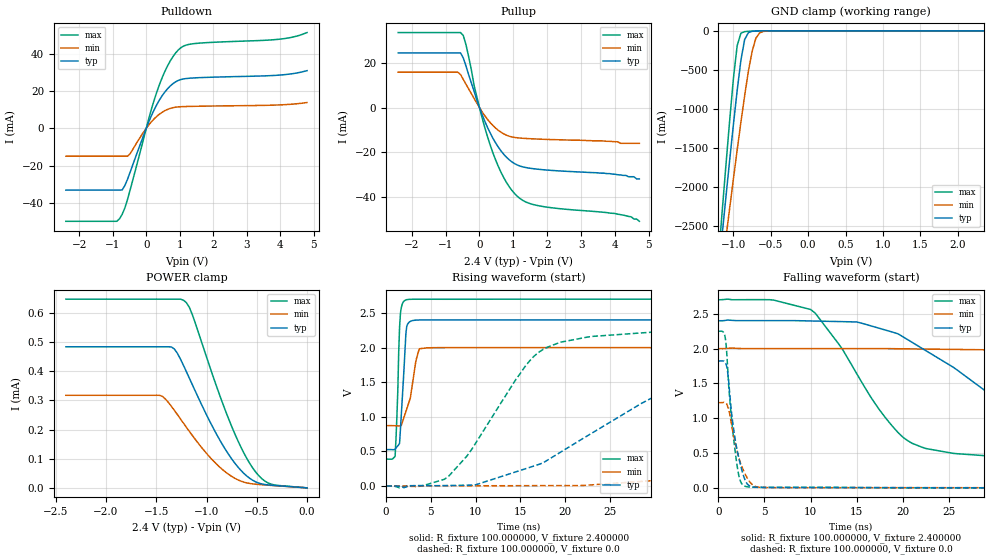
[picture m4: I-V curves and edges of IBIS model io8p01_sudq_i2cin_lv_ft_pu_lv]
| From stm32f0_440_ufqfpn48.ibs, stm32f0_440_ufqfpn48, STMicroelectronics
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|   Model io8p01_sudq_i2cin_lv_ft_pu_lv
[Model]  io8p01_sudq_i2cin_lv_ft_pu_lv
Model_type I/O
Polarity   Non-Inverting
Enable   Active-Low
Vinl =   0.720000V
Vinh =   1.680000V
Vmeas =  1.200000V
Cref =   50.000000pF
Rref =   100.000000M
Vref =   0.0V
C_comp   2.067900pF   1.988600pF   2.164800pF
[Temperature Range]   25.000000   0.125000k   -40.000000
[Pullup Reference]   2.400000V   2.000000V   2.700000V
[Pulldown Reference]   0.0V   0.0V   0.0V
[POWER Clamp Reference]   2.400000V   2.000000V   2.700000V
[GND Clamp Reference]   0.0V   0.0V   0.0V
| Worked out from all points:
|   slope of the pulldown table from 0 to 0.36 V, typ, clamps not added: 25.5 ohm
|   slope of the pullup table from 0 to 0.36 V, typ, clamps not added: 28.4 ohm
|   GND clamp passes 1 mA (typ) near -0.64 V on its own axis
|   rising waveform, R_fixture 100.000000, V_fixture 2.400000: 20-80 % time 499ps typ, 1.02ns min, 333ps max; typ from 0.527 V to 2.4 V
|   rising waveform, R_fixture 100.000000, V_fixture 0.0: 20-80 % time 14.6ns typ, 43.1ns min, 6.86ns max; typ from 0.001 V to 1.82 V
|   falling waveform, R_fixture 100.000000, V_fixture 2.400000: 20-80 % time 12.9ns typ, 32.3ns min, 7.06ns max; typ from 2.4 V to 0.527 V
|   falling waveform, R_fixture 100.000000, V_fixture 0.0: 20-80 % time 1.17ns typ, 1.4ns min, 925ps max; typ from 1.82 V to 0.001 V
[Pulldown]
|Voltage   I(typ)   I(min)   I(max)
-2.4V     -33.16mA   -14.98mA   -49.86mA
-880mV    -33.16mA   -14.98mA   -49.86mA
-800mV    -33.16mA   -14.98mA   -48.55mA
-640mV    -30.75mA   -14.98mA   -42.77mA
-480mV    -23.43mA   -13.57mA   -32.92mA
80mV      3.651mA    1.905mA    5.506mA
400mV     15.37mA    7.665mA    23.73mA
720mV     22.75mA    10.69mA    36.23mA
1.04V     26.18mA    11.57mA    43.27mA
1.52V     27.09mA    11.81mA    45.55mA
4V        28.55mA    12.55mA    47.81mA
4.8V      30.9mA     13.81mA    51.31mA
[Pullup]
|Voltage   I(typ)   I(min)   I(max)
-2.4V     24.56mA    15.9mA     33.69mA
-640mV    24.56mA    15.9mA     33.69mA
-480mV    22.33mA    12.71mA    32.43mA
-400mV    18.72mA    10.52mA    28.28mA
-160mV    7.425mA    4.163mA    10.02mA
0V        82fA       15.3pA     0A
320mV     -11.51mA   -6.781mA   -16.98mA
720mV     -21mA      -11.8mA    -31.53mA
1.2V      -26.24mA   -13.65mA   -40.82mA
1.76V     -27.69mA   -14.12mA   -44.06mA
4V        -29.9mA    -15.3mA    -47.5mA
4.72V     -32mA      -16mA      -51mA
[GND_clamp]
|Voltage   I(typ)   I(min)   I(max)
-2.4V     -9.567A    -9.921A    -9.731A
-1.2V     -3.09A     -3.428A    -2.911A
-1.15V    -2.606A    -3.04A     -2.31A
-1.1V     -2.127A    -2.655A    -1.719A
-1.05V    -1.657A    -2.274A    -1.146A
-950mV    -765.3mA   -1.53A     -190.2mA
-900mV    -376.6mA   -1.172A    -30.81mA
-850mV    -112.3mA   -832.5mA   -10.23mA
-750mV    -6.57mA    -264.6mA   -4.026mA
-700mV    -2.581mA   -94.26mA   -2.329mA
-600mV    -416.4uA   -8.158mA   -368uA
2.35V     0A         0A         0A
[POWER_clamp]
|Voltage   I(typ)   I(min)   I(max)
-2.4V     483.6uA    317.3uA    647uA
-1.47V    483.6uA    317.3uA    647uA
-1.32V    475.8uA    265.5uA    647uA
-1.23V    420.2uA    221.8uA    643.4uA
-1.17V    375.2uA    193uA      618uA
-1.14V    352.5uA    178.9uA    592.4uA
-840mV    147.3uA    62.31uA    290.1uA
-690mV    72.45uA    27.82uA    163.1uA
-540mV    25.82uA    13.54uA    67.87uA
-450mV    13.39uA    10.73uA    31.49uA
-360mV    9.214uA    8.518uA    13uA
0V        0A         0A         0A
[Ramp]
| variable   typ   min   max
dV/dt_r  1.09263/14.62764n   0.73353/43.01797n   1.34920/6.83604n
dV/dt_f  1.12405/12.83922n   0.67623/32.31165n   1.38687/7.04632n
R_load = 100.000000
[Rising Waveform]
R_fixture= 100.000000
V_fixture= 2.400000
V_fixture_min= 2.000000
V_fixture_max= 2.700000
|time   V(typ)   V(min)   V(max)
0s        526.5mV    872.5mV    388.6mV
1.001ns   534.7mV    870.8mV    428.9mV
1.301ns   581.2mV    869.2mV    1.377V
1.401ns   596.7mV    868.8mV    1.935V
1.502ns   619.6mV    868.5mV    2.301V
1.702ns   1.052V     879.1mV    2.584V
2.202ns   2.2V       1.075V     2.688V
2.603ns   2.371V     1.233V     2.697V
3.704ns   2.399V     1.983V     2.698V
49.85ns   2.4V       2V         2.7V
[Rising Waveform]
R_fixture= 100.000000
V_fixture= 0.0
V_fixture_min= 0.0
V_fixture_max= 0.0
|time   V(typ)   V(min)   V(max)
0s        1.055mV    1.354mV    939.9uV
7.007ns   7.848mV    4.649mV    146mV
15.52ns   248.4mV    5.734mV    1.727V
17.52ns   334.8mV    6.447mV    1.972V
29.03ns   1.229V     71.31mV    2.217V
35.04ns   1.569V     124.9mV    2.233V
43.04ns   1.723V     228.3mV    2.248V
88.59ns   1.821V     1.003V     2.25V
102.1ns   1.822V     1.112V     2.25V
249.2ns   1.822V     1.224V     2.25V
[Falling Waveform]
R_fixture= 100.000000
V_fixture= 2.400000
V_fixture_min= 2.000000
V_fixture_max= 2.700000
|time   V(typ)   V(min)   V(max)
0s        2.4V       2V         2.7V
10.01ns   2.397V     2V         2.562V
19.02ns   2.233V     1.999V     867.7mV
22.52ns   1.972V     1.993V     566.2mV
31.53ns   1.148V     1.979V     439mV
36.54ns   811.2mV    1.949V     422mV
45.05ns   647.7mV    1.835V     401.5mV
70.07ns   549.4mV    1.257V     389.2mV
86.09ns   537.9mV    1.038V     388.7mV
249.2ns   526.5mV    872.5mV    388.6mV
[Falling Waveform]
R_fixture= 100.000000
V_fixture= 0.0
V_fixture_min= 0.0
V_fixture_max= 0.0
|time   V(typ)   V(min)   V(max)
0s        1.822V     1.224V     2.25V
700.7ps   1.803V     1.224V     2.181V
1.001ns   1.657V     1.167V     1.711V
1.401ns   1.099V     927.6mV    1.011V
1.902ns   626.5mV    598.3mV    434mV
2.302ns   378.8mV    394.6mV    128.3mV
2.903ns   108.9mV    197.9mV    23.37mV
3.704ns   15.74mV    42.79mV    9.839mV
5.005ns   7.059mV    5.796mV    8.385mV
49.85ns   1.055mV    1.354mV    939.9uV
